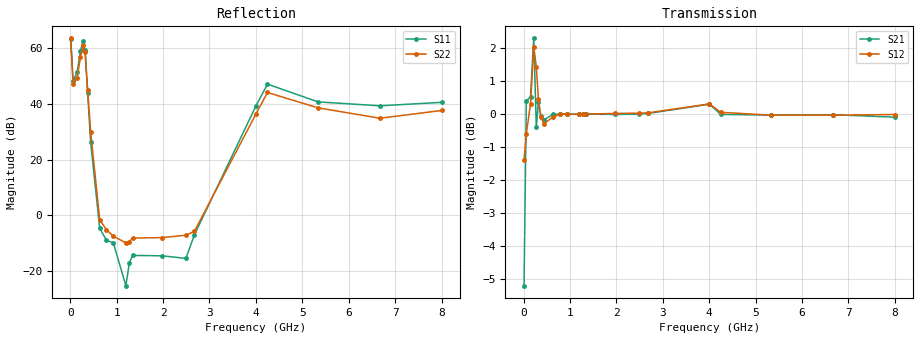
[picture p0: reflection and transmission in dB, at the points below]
!Agilent Technologies,N5230A,US43500312,A.07.50.67
!Agilent N5230A: A.07.50.67
!Date: Tuesday, June 09, 2015 15:33:41
!Correction: S11(Full 2 Port(1,2))
!S21(Full 2 Port(1,2))
!S12(Full 2 Port(1,2))
!S22(Full 2 Port(1,2))
!S2P File: Measurements: S11, S21, S12, S22:
# Hz S  MA  R 50
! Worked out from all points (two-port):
!   1601 points, 10 MHz to 8 GHz, reference 50 ohm
!   highest |S21| = 2.29 dB at 219.7 MHz (marker M1); lowest = -5.2 dB at 10 MHz (marker M2)
!   |S21| within 3 dB of the highest: 68.04 MHz to 224.7 MHz (156.6 MHz wide, 107 % of centre); 304.2 MHz to end of sweep (the widest 2 of 8)
!   lowest |S11| = -25.4 dB at 1.199 GHz (marker M3), VSWR 1.11, Z = 54.5 + j3.31 ohm
!   |S11| at or under -10 dB: 788.4 MHz to 930.8 MHz (142.4 MHz wide, 16.6 % of centre); 1.046 GHz to 2.087 GHz (1.041 GHz wide, 66.5 % of centre); 2.366 GHz to 2.616 GHz (249.1 MHz wide, 10 % of centre) (the widest 3 of 4)
!   |S22| runs from -13.9 to 63.6 dB; largest |S21 - S12| = 0.51
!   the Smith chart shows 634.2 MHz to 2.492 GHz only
!   S11 on the Smith chart (normalised r, x): 634.2 MHz: 0.38, +0.62; 779 MHz: 0.49, +0.17; 928.9 MHz: 0.91, -0.62; 1.273 GHz: 0.91, +0.25; 1.978 GHz: 0.71, +0.12; 2.492 GHz: 0.73, -0.11
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1e7  1500 171.1  0.5496 -59.7  0.8526 -94.1  1521 -19.5
5.99375e7  257.7 325.7  1.047 0.7  0.9342 -1.2  233 92.2
1.49825e8  380.3 391.4  1.062 1.4  1.036 1.5  299.3 116.6
2.197375e8  899.1 405.1  1.302 7.6  1.264 9.6  700.8 121.5
2.746688e8  1372 390.2  0.9547 18.1  1.179 -0.2  1136 108.6
3.196125e8  927.4 420.0  1.042 8.9  1.054 -6.0  848.9 145.1
3.745438e8  160.8 431.9  0.9921 1.6  0.9893 -0.7  179.9 174.9
4.394625e8  20.43 410.7  0.98 0.7  0.9669 0.7  31.54 194.4
6.342188e8  0.5782 470.3  0.9988 1.0  0.9896 1.1  0.8279 373.2
7.790375e8  0.3543 514.8  0.9995 0.8  0.9995 0.6  0.5449 452.6
9.2885e8  0.3135 639.4  1 0.8  0.9993 0.8  0.4182 576.7
1.198512e9  0.05359 754.4  1 0.8  0.999 1.0  0.3162 686.4
1.273419e9  0.1384 822.9  0.9991 0.8  0.9993 0.9  0.3336 733.3
1.343331e9  0.1881 836.5  1 0.8  0.9999 0.8  0.3859 762.6
1.977538e9  0.1851 874.1  0.9986 0.8  1.002 0.8  0.3936 1028.3
2.491894e9  0.1662 926.0  0.9998 0.9  1.003 0.9  0.4344 1150.5
2.676662e9  0.445 1014.8  1.002 0.9  1.004 0.9  0.5128 1231.2
4.005e9  93.82 1390.9  1.035 -0.2  1.036 0.1  67.06 1520.2
4.249694e9  228.2 1341.4  0.9987 -0.3  1.006 -0.5  161.3 1459.9
5.338331e9  109.3 1319.0  0.9963 0.0  0.9961 -0.0  85.35 1399.4
6.671662e9  92.84 1357.1  0.9977 0.3  0.9962 0.2  55.47 1338.6
8e9  107.2 1385.9  0.9892 0.4  0.9984 0.2  76.45 1306.9
